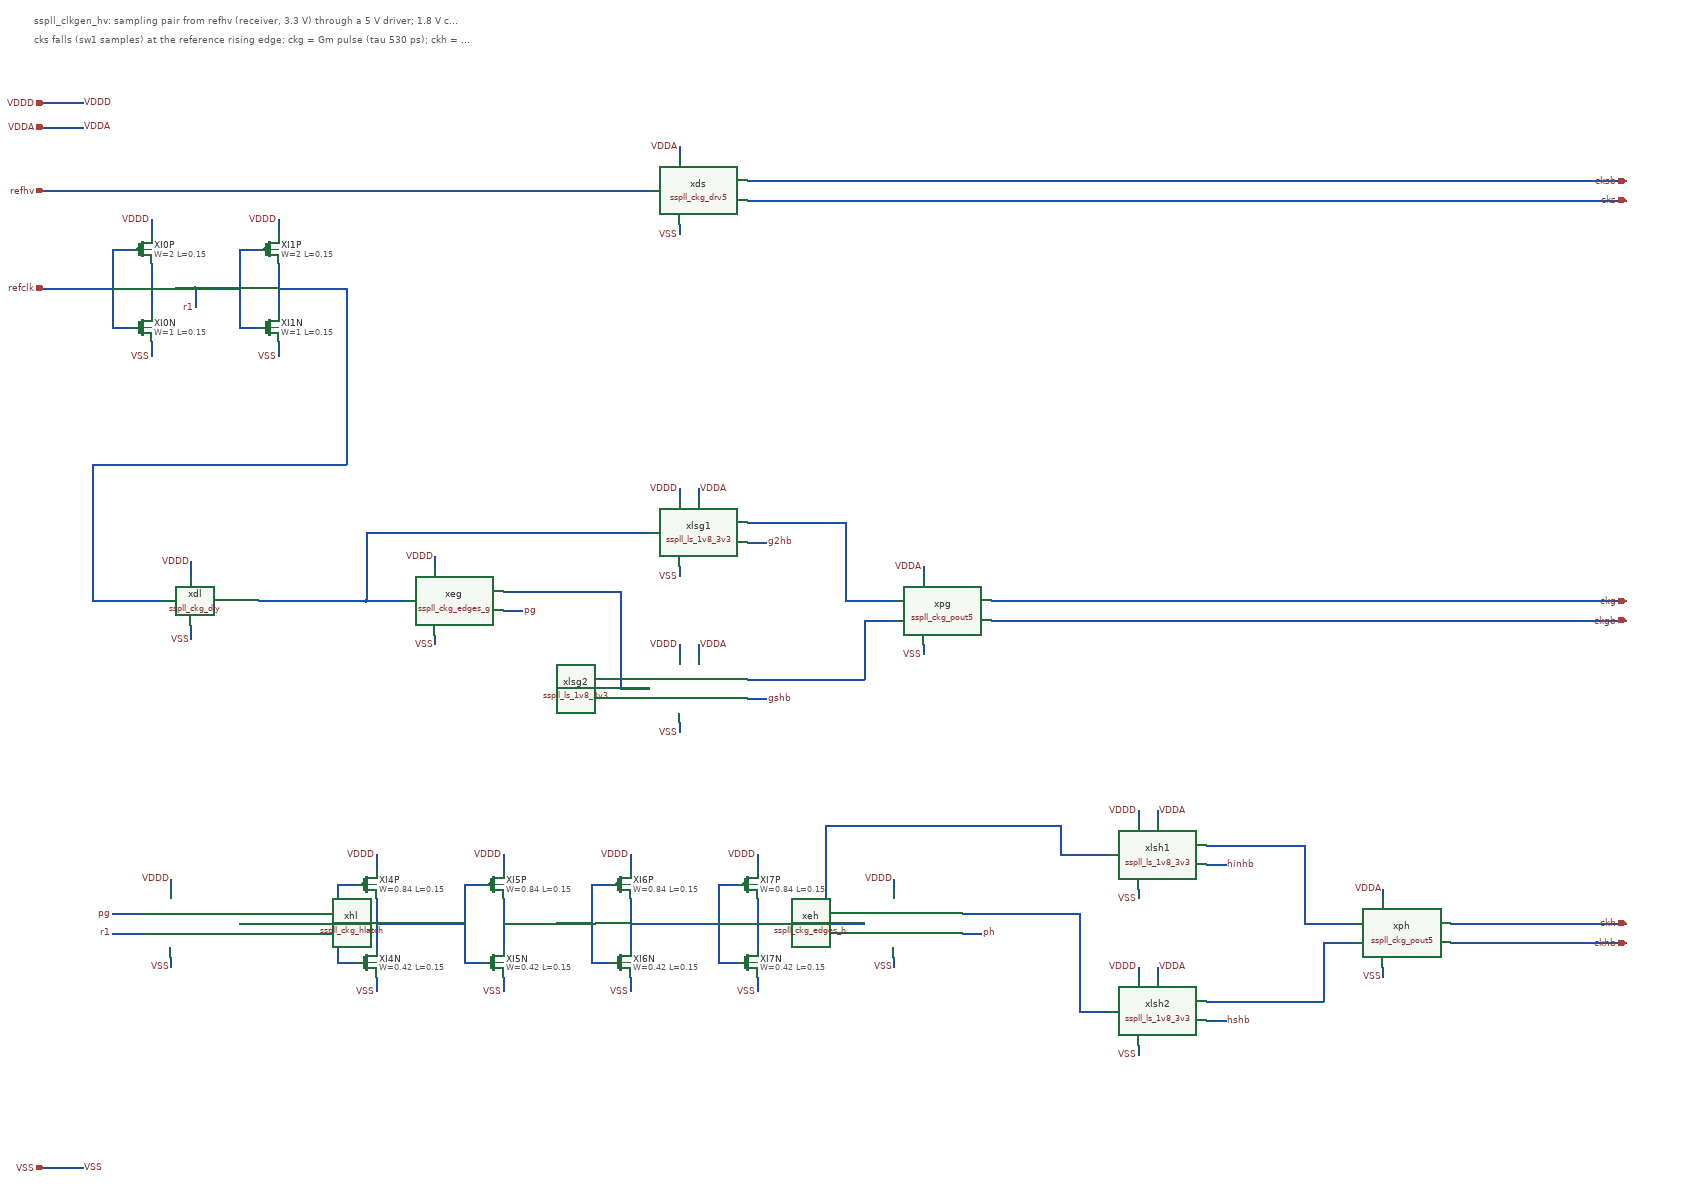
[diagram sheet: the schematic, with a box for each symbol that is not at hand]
v {xschem version=3.4.4 file_version=1.2}
G {}
K {}
V {}
S {}
E {}
T {sspll_clkgen_hv: sampling pair from refhv (receiver, 3.3 V) through a 5 V driver; 1.8 V core on VDDD (refclk buffer, gap inverters, RC edge pairs, hold latch); each pulse crosses to VDDA as two rising steps and is formed at the 5 V output gates} 40 -560 0 0 0.3 0.3 {}
T {cks falls (sw1 samples) at the reference rising edge; ckg = Gm pulse (tau 530 ps); ckh = hold pulse; supplies of the sub-cells and internal nets joined by name} 40 -520 0 0 0.25 0.25 {}
N 280 -50 280 50 {lab=}
N 240 -80 200 -80 {lab=}
N 200 -80 200 80 {lab=}
N 200 80 240 80 {lab=}
N 280 -110 280 -140 {lab=}
N 280 110 280 140 {lab=}
N 540 -50 540 50 {lab=}
N 500 -80 460 -80 {lab=}
N 460 -80 460 80 {lab=}
N 460 80 500 80 {lab=}
N 540 -110 540 -140 {lab=}
N 540 110 540 140 {lab=}
N 60 0 200 0 {lab=}
N 280 0 370 0 {lab=}
N 370 0 460 0 {lab=}
N 370 0 370 40 {lab=}
N 540 0 680 0 {lab=}
N 60 -200 1000 -200 {lab=}
N 1000 -200 1300 -200 {lab=}
N 680 0 680 360 {lab=}
N 680 360 160 360 {lab=}
N 160 360 160 640 {lab=}
N 160 640 300 640 {lab=}
N 360 590 360 560 {lab=}
N 360 690 360 720 {lab=}
N 500 640 720 640 {lab=}
N 720 640 800 640 {lab=}
N 720 640 720 500 {lab=}
N 720 500 1200 500 {lab=}
N 1200 500 1300 500 {lab=}
N 1000 620 1240 620 {lab=}
N 1240 620 1240 820 {lab=}
N 1240 820 1300 820 {lab=}
N 1500 480 1700 480 {lab=}
N 1700 480 1700 640 {lab=}
N 1700 640 1800 640 {lab=}
N 1500 800 1740 800 {lab=}
N 1740 800 1740 680 {lab=}
N 1740 680 1800 680 {lab=}
N 1000 660 1040 660 {lab=}
N 260 1280 200 1280 {lab=}
N 260 1320 200 1320 {lab=}
N 740 1250 740 1350 {lab=}
N 700 1220 660 1220 {lab=}
N 660 1220 660 1380 {lab=}
N 660 1380 700 1380 {lab=}
N 740 1190 740 1160 {lab=}
N 740 1410 740 1440 {lab=}
N 1000 1250 1000 1350 {lab=}
N 960 1220 920 1220 {lab=}
N 920 1220 920 1380 {lab=}
N 920 1380 960 1380 {lab=}
N 1000 1190 1000 1160 {lab=}
N 1000 1410 1000 1440 {lab=}
N 1260 1250 1260 1350 {lab=}
N 1220 1220 1180 1220 {lab=}
N 1180 1220 1180 1380 {lab=}
N 1180 1380 1220 1380 {lab=}
N 1260 1190 1260 1160 {lab=}
N 1260 1410 1260 1440 {lab=}
N 1520 1250 1520 1350 {lab=}
N 1480 1220 1440 1220 {lab=}
N 1440 1220 1440 1380 {lab=}
N 1440 1380 1480 1380 {lab=}
N 1520 1190 1520 1160 {lab=}
N 1520 1410 1520 1440 {lab=}
N 460 1300 620 1300 {lab=}
N 620 1300 660 1300 {lab=}
N 740 1300 920 1300 {lab=}
N 1000 1300 1180 1300 {lab=}
N 1260 1300 1440 1300 {lab=}
N 1520 1300 1660 1300 {lab=}
N 1660 1300 1740 1300 {lab=}
N 1660 1300 1660 1100 {lab=}
N 1660 1100 2140 1100 {lab=}
N 2140 1100 2140 1160 {lab=}
N 2140 1160 2240 1160 {lab=}
N 1940 1280 2180 1280 {lab=}
N 2180 1280 2180 1480 {lab=}
N 2180 1480 2240 1480 {lab=}
N 1940 1320 1980 1320 {lab=}
N 2440 1140 2640 1140 {lab=}
N 2640 1140 2640 1300 {lab=}
N 2640 1300 2740 1300 {lab=}
N 2440 1460 2680 1460 {lab=}
N 2680 1460 2680 1340 {lab=}
N 2680 1340 2740 1340 {lab=}
N 1500 520 1540 520 {lab=}
N 1500 840 1540 840 {lab=}
N 2440 1180 2480 1180 {lab=}
N 2440 1500 2480 1500 {lab=}
N 1500 -220 3300 -220 {lab=}
N 1500 -180 3300 -180 {lab=}
N 2000 640 3300 640 {lab=}
N 2000 680 3300 680 {lab=}
N 2940 1300 3300 1300 {lab=}
N 2940 1340 3300 1340 {lab=}
N 1360 430 1360 410 {lab=}
N 1400 430 1400 410 {lab=}
N 1360 750 1360 730 {lab=}
N 1400 750 1400 730 {lab=}
N 2300 1090 2300 1070 {lab=}
N 2340 1090 2340 1070 {lab=}
N 2300 1410 2300 1390 {lab=}
N 2340 1410 2340 1390 {lab=}
N 1360 -270 1360 -290 {lab=}
N 1860 590 1860 570 {lab=}
N 2800 1250 2800 1230 {lab=}
N 860 570 860 550 {lab=}
N 1800 1230 1800 1210 {lab=}
N 320 1230 320 1210 {lab=}
N 1360 570 1360 590 {lab=}
N 1360 890 1360 910 {lab=}
N 2300 1230 2300 1250 {lab=}
N 2300 1550 2300 1570 {lab=}
N 1360 -130 1360 -110 {lab=}
N 1860 730 1860 750 {lab=}
N 2800 1390 2800 1410 {lab=}
N 860 710 860 730 {lab=}
N 1800 1370 1800 1390 {lab=}
N 320 1370 320 1390 {lab=}
N 60 -380 140 -380 {lab=}
N 60 -330 140 -330 {lab=}
N 60 1800 140 1800 {lab=}
C {devices/ipin.sym} 60 0 0 0 {name=p_refclk lab=refclk}
C {sky130_fd_pr/pfet3_01v8.sym} 260 -80 0 0 {name=XI0P L=0.15 W=2 nf=1 mult=1 ad="'int((nf+1)/2) * W/nf * 0.29'" pd="'2*int((nf+1)/2) * (W/nf + 0.29)'" as="'int((nf+2)/2) * W/nf * 0.29'" ps="'2*int((nf+2)/2) * (W/nf + 0.29)'" nrd="'0.29 / W'" nrs="'0.29 / W'" sa=0 sb=0 sd=0 model=pfet_01v8 spiceprefix=X body=VDDD}
C {sky130_fd_pr/nfet3_01v8.sym} 260 80 0 0 {name=XI0N L=0.15 W=1 nf=1 mult=1 ad="'int((nf+1)/2) * W/nf * 0.29'" pd="'2*int((nf+1)/2) * (W/nf + 0.29)'" as="'int((nf+2)/2) * W/nf * 0.29'" ps="'2*int((nf+2)/2) * (W/nf + 0.29)'" nrd="'0.29 / W'" nrs="'0.29 / W'" sa=0 sb=0 sd=0 model=nfet_01v8 spiceprefix=X body=VSS}
C {devices/lab_pin.sym} 280 -140 0 0 {name=l_VDDD_3 sig_type=std_logic lab=VDDD}
C {devices/lab_pin.sym} 280 140 0 0 {name=l_VSS_4 sig_type=std_logic lab=VSS}
C {sky130_fd_pr/pfet3_01v8.sym} 520 -80 0 0 {name=XI1P L=0.15 W=2 nf=1 mult=1 ad="'int((nf+1)/2) * W/nf * 0.29'" pd="'2*int((nf+1)/2) * (W/nf + 0.29)'" as="'int((nf+2)/2) * W/nf * 0.29'" ps="'2*int((nf+2)/2) * (W/nf + 0.29)'" nrd="'0.29 / W'" nrs="'0.29 / W'" sa=0 sb=0 sd=0 model=pfet_01v8 spiceprefix=X body=VDDD}
C {sky130_fd_pr/nfet3_01v8.sym} 520 80 0 0 {name=XI1N L=0.15 W=1 nf=1 mult=1 ad="'int((nf+1)/2) * W/nf * 0.29'" pd="'2*int((nf+1)/2) * (W/nf + 0.29)'" as="'int((nf+2)/2) * W/nf * 0.29'" ps="'2*int((nf+2)/2) * (W/nf + 0.29)'" nrd="'0.29 / W'" nrs="'0.29 / W'" sa=0 sb=0 sd=0 model=nfet_01v8 spiceprefix=X body=VSS}
C {devices/lab_pin.sym} 540 -140 0 0 {name=l_VDDD_7 sig_type=std_logic lab=VDDD}
C {devices/lab_pin.sym} 540 140 0 0 {name=l_VSS_8 sig_type=std_logic lab=VSS}
C {devices/lab_pin.sym} 370 40 0 0 {name=l_r1_9 sig_type=std_logic lab=r1}
C {devices/ipin.sym} 60 -200 0 0 {name=p_refhv lab=refhv}
C {sspll_ckg_drv5.sym} 1400 -200 0 0 {name=xds}
C {sspll_ckg_dly.sym} 400 640 0 0 {name=xdl}
C {devices/lab_pin.sym} 360 560 0 0 {name=l_VDDD_13 sig_type=std_logic lab=VDDD}
C {devices/lab_pin.sym} 360 720 0 0 {name=l_VSS_14 sig_type=std_logic lab=VSS}
C {sspll_ckg_edges_g.sym} 900 640 0 0 {name=xeg}
C {../cco_hv/sspll_ls_1v8_3v3.sym} 1400 500 0 0 {name=xlsg1}
C {../cco_hv/sspll_ls_1v8_3v3.sym} 1400 820 0 0 {name=xlsg2}
C {sspll_ckg_pout5.sym} 1900 660 0 0 {name=xpg}
C {devices/lab_pin.sym} 1040 660 0 1 {name=l_pg_19 sig_type=std_logic lab=pg}
C {sspll_ckg_hlatch.sym} 360 1300 0 0 {name=xhl}
C {devices/lab_pin.sym} 200 1280 0 0 {name=l_pg_21 sig_type=std_logic lab=pg}
C {devices/lab_pin.sym} 200 1320 0 0 {name=l_r1_22 sig_type=std_logic lab=r1}
C {sky130_fd_pr/pfet3_01v8.sym} 720 1220 0 0 {name=XI4P L=0.15 W=0.84 nf=1 mult=1 ad="'int((nf+1)/2) * W/nf * 0.29'" pd="'2*int((nf+1)/2) * (W/nf + 0.29)'" as="'int((nf+2)/2) * W/nf * 0.29'" ps="'2*int((nf+2)/2) * (W/nf + 0.29)'" nrd="'0.29 / W'" nrs="'0.29 / W'" sa=0 sb=0 sd=0 model=pfet_01v8 spiceprefix=X body=VDDD}
C {sky130_fd_pr/nfet3_01v8.sym} 720 1380 0 0 {name=XI4N L=0.15 W=0.42 nf=1 mult=1 ad="'int((nf+1)/2) * W/nf * 0.29'" pd="'2*int((nf+1)/2) * (W/nf + 0.29)'" as="'int((nf+2)/2) * W/nf * 0.29'" ps="'2*int((nf+2)/2) * (W/nf + 0.29)'" nrd="'0.29 / W'" nrs="'0.29 / W'" sa=0 sb=0 sd=0 model=nfet_01v8 spiceprefix=X body=VSS}
C {devices/lab_pin.sym} 740 1160 0 0 {name=l_VDDD_25 sig_type=std_logic lab=VDDD}
C {devices/lab_pin.sym} 740 1440 0 0 {name=l_VSS_26 sig_type=std_logic lab=VSS}
C {sky130_fd_pr/pfet3_01v8.sym} 980 1220 0 0 {name=XI5P L=0.15 W=0.84 nf=1 mult=1 ad="'int((nf+1)/2) * W/nf * 0.29'" pd="'2*int((nf+1)/2) * (W/nf + 0.29)'" as="'int((nf+2)/2) * W/nf * 0.29'" ps="'2*int((nf+2)/2) * (W/nf + 0.29)'" nrd="'0.29 / W'" nrs="'0.29 / W'" sa=0 sb=0 sd=0 model=pfet_01v8 spiceprefix=X body=VDDD}
C {sky130_fd_pr/nfet3_01v8.sym} 980 1380 0 0 {name=XI5N L=0.15 W=0.42 nf=1 mult=1 ad="'int((nf+1)/2) * W/nf * 0.29'" pd="'2*int((nf+1)/2) * (W/nf + 0.29)'" as="'int((nf+2)/2) * W/nf * 0.29'" ps="'2*int((nf+2)/2) * (W/nf + 0.29)'" nrd="'0.29 / W'" nrs="'0.29 / W'" sa=0 sb=0 sd=0 model=nfet_01v8 spiceprefix=X body=VSS}
C {devices/lab_pin.sym} 1000 1160 0 0 {name=l_VDDD_29 sig_type=std_logic lab=VDDD}
C {devices/lab_pin.sym} 1000 1440 0 0 {name=l_VSS_30 sig_type=std_logic lab=VSS}
C {sky130_fd_pr/pfet3_01v8.sym} 1240 1220 0 0 {name=XI6P L=0.15 W=0.84 nf=1 mult=1 ad="'int((nf+1)/2) * W/nf * 0.29'" pd="'2*int((nf+1)/2) * (W/nf + 0.29)'" as="'int((nf+2)/2) * W/nf * 0.29'" ps="'2*int((nf+2)/2) * (W/nf + 0.29)'" nrd="'0.29 / W'" nrs="'0.29 / W'" sa=0 sb=0 sd=0 model=pfet_01v8 spiceprefix=X body=VDDD}
C {sky130_fd_pr/nfet3_01v8.sym} 1240 1380 0 0 {name=XI6N L=0.15 W=0.42 nf=1 mult=1 ad="'int((nf+1)/2) * W/nf * 0.29'" pd="'2*int((nf+1)/2) * (W/nf + 0.29)'" as="'int((nf+2)/2) * W/nf * 0.29'" ps="'2*int((nf+2)/2) * (W/nf + 0.29)'" nrd="'0.29 / W'" nrs="'0.29 / W'" sa=0 sb=0 sd=0 model=nfet_01v8 spiceprefix=X body=VSS}
C {devices/lab_pin.sym} 1260 1160 0 0 {name=l_VDDD_33 sig_type=std_logic lab=VDDD}
C {devices/lab_pin.sym} 1260 1440 0 0 {name=l_VSS_34 sig_type=std_logic lab=VSS}
C {sky130_fd_pr/pfet3_01v8.sym} 1500 1220 0 0 {name=XI7P L=0.15 W=0.84 nf=1 mult=1 ad="'int((nf+1)/2) * W/nf * 0.29'" pd="'2*int((nf+1)/2) * (W/nf + 0.29)'" as="'int((nf+2)/2) * W/nf * 0.29'" ps="'2*int((nf+2)/2) * (W/nf + 0.29)'" nrd="'0.29 / W'" nrs="'0.29 / W'" sa=0 sb=0 sd=0 model=pfet_01v8 spiceprefix=X body=VDDD}
C {sky130_fd_pr/nfet3_01v8.sym} 1500 1380 0 0 {name=XI7N L=0.15 W=0.42 nf=1 mult=1 ad="'int((nf+1)/2) * W/nf * 0.29'" pd="'2*int((nf+1)/2) * (W/nf + 0.29)'" as="'int((nf+2)/2) * W/nf * 0.29'" ps="'2*int((nf+2)/2) * (W/nf + 0.29)'" nrd="'0.29 / W'" nrs="'0.29 / W'" sa=0 sb=0 sd=0 model=nfet_01v8 spiceprefix=X body=VSS}
C {devices/lab_pin.sym} 1520 1160 0 0 {name=l_VDDD_37 sig_type=std_logic lab=VDDD}
C {devices/lab_pin.sym} 1520 1440 0 0 {name=l_VSS_38 sig_type=std_logic lab=VSS}
C {sspll_ckg_edges_h.sym} 1840 1300 0 0 {name=xeh}
C {../cco_hv/sspll_ls_1v8_3v3.sym} 2340 1160 0 0 {name=xlsh1}
C {../cco_hv/sspll_ls_1v8_3v3.sym} 2340 1480 0 0 {name=xlsh2}
C {devices/lab_pin.sym} 1980 1320 0 1 {name=l_ph_42 sig_type=std_logic lab=ph}
C {sspll_ckg_pout5.sym} 2840 1320 0 0 {name=xph}
C {devices/lab_pin.sym} 1540 520 0 1 {name=l_g2hb_44 sig_type=std_logic lab=g2hb}
C {devices/lab_pin.sym} 1540 840 0 1 {name=l_gshb_45 sig_type=std_logic lab=gshb}
C {devices/lab_pin.sym} 2480 1180 0 1 {name=l_hinhb_46 sig_type=std_logic lab=hinhb}
C {devices/lab_pin.sym} 2480 1500 0 1 {name=l_hshb_47 sig_type=std_logic lab=hshb}
C {devices/opin.sym} 3300 -220 0 1 {name=p_cksb lab=cksb}
C {devices/opin.sym} 3300 -180 0 1 {name=p_cks lab=cks}
C {devices/opin.sym} 3300 640 0 1 {name=p_ckg lab=ckg}
C {devices/opin.sym} 3300 680 0 1 {name=p_ckgb lab=ckgb}
C {devices/opin.sym} 3300 1300 0 1 {name=p_ckh lab=ckh}
C {devices/opin.sym} 3300 1340 0 1 {name=p_ckhb lab=ckhb}
C {devices/lab_pin.sym} 1360 410 0 0 {name=l_VDDD_54 sig_type=std_logic lab=VDDD}
C {devices/lab_pin.sym} 1400 410 0 1 {name=l_VDDA_55 sig_type=std_logic lab=VDDA}
C {devices/lab_pin.sym} 1360 730 0 0 {name=l_VDDD_56 sig_type=std_logic lab=VDDD}
C {devices/lab_pin.sym} 1400 730 0 1 {name=l_VDDA_57 sig_type=std_logic lab=VDDA}
C {devices/lab_pin.sym} 2300 1070 0 0 {name=l_VDDD_58 sig_type=std_logic lab=VDDD}
C {devices/lab_pin.sym} 2340 1070 0 1 {name=l_VDDA_59 sig_type=std_logic lab=VDDA}
C {devices/lab_pin.sym} 2300 1390 0 0 {name=l_VDDD_60 sig_type=std_logic lab=VDDD}
C {devices/lab_pin.sym} 2340 1390 0 1 {name=l_VDDA_61 sig_type=std_logic lab=VDDA}
C {devices/lab_pin.sym} 1360 -290 0 0 {name=l_VDDA_62 sig_type=std_logic lab=VDDA}
C {devices/lab_pin.sym} 1860 570 0 0 {name=l_VDDA_63 sig_type=std_logic lab=VDDA}
C {devices/lab_pin.sym} 2800 1230 0 0 {name=l_VDDA_64 sig_type=std_logic lab=VDDA}
C {devices/lab_pin.sym} 860 550 0 0 {name=l_VDDD_65 sig_type=std_logic lab=VDDD}
C {devices/lab_pin.sym} 1800 1210 0 0 {name=l_VDDD_66 sig_type=std_logic lab=VDDD}
C {devices/lab_pin.sym} 320 1210 0 0 {name=l_VDDD_67 sig_type=std_logic lab=VDDD}
C {devices/lab_pin.sym} 1360 590 0 0 {name=l_VSS_68 sig_type=std_logic lab=VSS}
C {devices/lab_pin.sym} 1360 910 0 0 {name=l_VSS_69 sig_type=std_logic lab=VSS}
C {devices/lab_pin.sym} 2300 1250 0 0 {name=l_VSS_70 sig_type=std_logic lab=VSS}
C {devices/lab_pin.sym} 2300 1570 0 0 {name=l_VSS_71 sig_type=std_logic lab=VSS}
C {devices/lab_pin.sym} 1360 -110 0 0 {name=l_VSS_72 sig_type=std_logic lab=VSS}
C {devices/lab_pin.sym} 1860 750 0 0 {name=l_VSS_73 sig_type=std_logic lab=VSS}
C {devices/lab_pin.sym} 2800 1410 0 0 {name=l_VSS_74 sig_type=std_logic lab=VSS}
C {devices/lab_pin.sym} 860 730 0 0 {name=l_VSS_75 sig_type=std_logic lab=VSS}
C {devices/lab_pin.sym} 1800 1390 0 0 {name=l_VSS_76 sig_type=std_logic lab=VSS}
C {devices/lab_pin.sym} 320 1390 0 0 {name=l_VSS_77 sig_type=std_logic lab=VSS}
C {devices/iopin.sym} 60 -380 0 0 {name=p_VDDD lab=VDDD}
C {devices/lab_pin.sym} 140 -380 0 1 {name=l_VDDD_79 sig_type=std_logic lab=VDDD}
C {devices/iopin.sym} 60 -330 0 0 {name=p_VDDA lab=VDDA}
C {devices/lab_pin.sym} 140 -330 0 1 {name=l_VDDA_81 sig_type=std_logic lab=VDDA}
C {devices/iopin.sym} 60 1800 0 0 {name=p_VSS lab=VSS}
C {devices/lab_pin.sym} 140 1800 0 1 {name=l_VSS_83 sig_type=std_logic lab=VSS}
